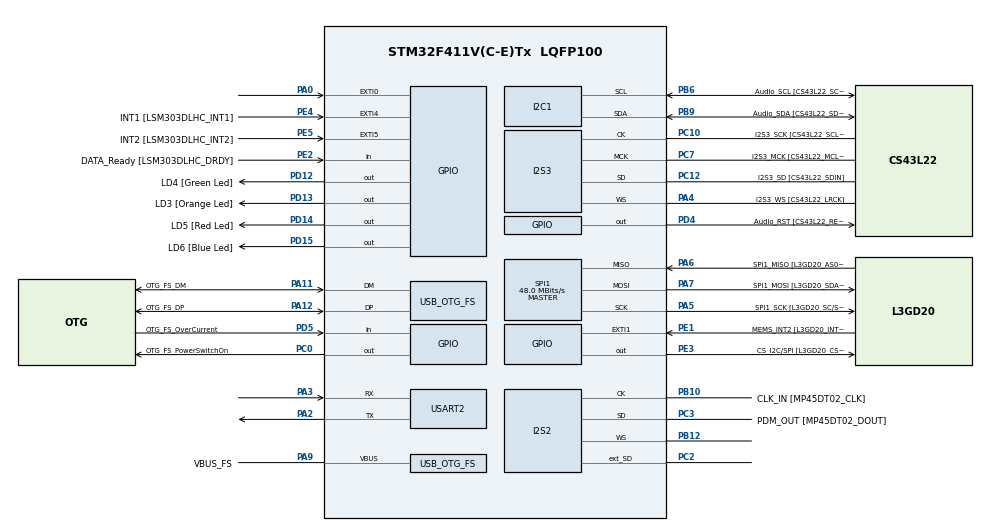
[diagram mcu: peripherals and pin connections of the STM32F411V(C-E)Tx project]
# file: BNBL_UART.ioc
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I2S2.AudioFreq=I2S_AUDIOFREQ_96K
I2S2.ErrorAudioFreq=0.15 %
I2S2.FullDuplexMode=I2S_FULLDUPLEXMODE_ENABLE
I2S2.Instance=SPI$Index
I2S2.RealAudioFreq=96.153 KHz
I2S2.VirtualMode=I2S_MODE_MASTER
I2S3.AudioFreq=I2S_AUDIOFREQ_96K
I2S3.ErrorAudioFreq=-6.99 %
I2S3.FullDuplexMode=I2S_FULLDUPLEXMODE_DISABLE
I2S3.Instance=SPI$Index
I2S3.RealAudioFreq=89.285 KHz
I2S3.VirtualMode=I2S_MODE_MASTER
Mcu.Family=STM32F4
Mcu.Name=STM32F411V(C-E)Tx
Mcu.Package=LQFP100
NVIC.OTG_FS_IRQn=true\:0\:0\:false\:false\:true\:true\:true\:true
NVIC.PriorityGroup=NVIC_PRIORITYGROUP_0
NVIC.USART2_IRQn=true\:0\:0\:false\:false\:true\:true\:true\:true
PA0-WKUP.GPIO_ModeDefaultEXTI=GPIO_MODE_EVT_RISING
PA0-WKUP.Signal=GPXTI0
PA10.GPIO_Label=OTG_FS_ID
PA10.Signal=USB_OTG_FS_ID
PA11.GPIO_Label=OTG_FS_DM
PA11.Mode=Device_Only
PA11.Signal=USB_OTG_FS_DM
PA12.GPIO_Label=OTG_FS_DP
PA12.Mode=Device_Only
PA12.Signal=USB_OTG_FS_DP
PA13.GPIO_Label=SWDIO
PA13.Mode=Serial_Wire
PA13.Signal=SYS_JTMS-SWDIO
PA14.GPIO_Label=SWCLK
PA14.Mode=Serial_Wire
PA14.Signal=SYS_JTCK-SWCLK
PA2.Mode=Asynchronous
PA2.Signal=USART2_TX
PA3.Mode=Asynchronous
PA3.Signal=USART2_RX
PA4.GPIO_Label=I2S3_WS [CS43L22_LRCK]
PA4.GPIO_Mode=GPIO_MODE_AF_PP
PA4.GPIO_PuPd=GPIO_NOPULL
PA4.GPIO_Speed=GPIO_SPEED_FREQ_LOW
PA4.Mode=Half_Duplex_Master
PA4.Signal=I2S3_WS
PA5.GPIO_Label=SPI1_SCK [L3GD20_SC/SPC]
PA5.Mode=Full_Duplex_Master
PA5.Signal=SPI1_SCK
PA6.GPIO_Label=SPI1_MISO [L3GD20_AS0/SDO]
PA6.Mode=Full_Duplex_Master
PA6.Signal=SPI1_MISO
PA7.GPIO_Label=SPI1_MOSI [L3GD20_SDA/SDI/SDO]
PA7.Mode=Full_Duplex_Master
PA7.Signal=SPI1_MOSI
PA9.GPIO_Label=VBUS_FS
PA9.Mode=Activate_VBUS
PA9.Signal=USB_OTG_FS_VBUS
PB10.GPIO_Label=CLK_IN [MP45DT02_CLK]
PB10.Mode=Full_Duplex_Master
PB10.Signal=I2S2_CK
PB12.Mode=Full_Duplex_Master
PB12.Signal=I2S2_WS
PB3.GPIO_Label=SWO
PB3.Signal=SYS_JTDO-SWO
PB6.GPIO_Label=Audio_SCL [CS43L22_SCL]
PB6.GPIO_Mode=GPIO_MODE_AF_OD
PB6.GPIO_Pu=GPIO_PULLUP
PB6.GPIO_PuPd=GPIO_NOPULL
PB6.GPIO_Speed=GPIO_SPEED_FREQ_LOW
PB6.Mode=I2C
PB6.Signal=I2C1_SCL
PB9.GPIO_Label=Audio_SDA [CS43L22_SDA]
PB9.GPIO_Mode=GPIO_MODE_AF_OD
PB9.GPIO_Pu=GPIO_PULLUP
PB9.GPIO_PuPd=GPIO_NOPULL
PB9.GPIO_Speed=GPIO_SPEED_FREQ_LOW
PB9.Mode=I2C
PB9.Signal=I2C1_SDA
PC0.GPIO_Label=OTG_FS_PowerSwitchOn
PC0.PinState=GPIO_PIN_SET
PC0.Signal=GPIO_Output
PC10.GPIO_Label=I2S3_SCK [CS43L22_SCLK]
PC10.GPIO_Mode=GPIO_MODE_AF_PP
PC10.GPIO_PuPd=GPIO_NOPULL
PC10.GPIO_Speed=GPIO_SPEED_FREQ_LOW
PC10.Mode=Half_Duplex_Master
PC10.Signal=I2S3_CK
PC12.GPIO_Label=I2S3_SD [CS43L22_SDIN]
PC12.GPIO_Mode=GPIO_MODE_AF_PP
PC12.GPIO_PuPd=GPIO_NOPULL
PC12.GPIO_Speed=GPIO_SPEED_FREQ_LOW
PC12.Mode=Half_Duplex_Master
PC12.Signal=I2S3_SD
PC14-OSC32_IN.GPIO_Label=PC14-OSC32_IN
PC14-OSC32_IN.Mode=LSE-External-Oscillator
PC14-OSC32_IN.Signal=RCC_OSC32_IN
PC15-OSC32_OUT.GPIO_Label=PC15-OSC32_OUT
PC15-OSC32_OUT.Mode=LSE-External-Oscillator
PC15-OSC32_OUT.Signal=RCC_OSC32_OUT
PC2.Mode=Full_Duplex_Master
PC2.Signal=I2S2_ext_SD
PC3.GPIO_Label=PDM_OUT [MP45DT02_DOUT]
PC3.Mode=Full_Duplex_Master
PC3.Signal=I2S2_SD
PC7.GPIO_Label=I2S3_MCK [CS43L22_MCLK]
PC7.GPIO_Mode=GPIO_MODE_AF_PP
PC7.GPIO_PuPd=GPIO_NOPULL
PC7.GPIO_Speed=GPIO_SPEED_FREQ_LOW
PC7.Mode=Master_Clock_Activated
PC7.Signal=I2S3_MCK
PD12.GPIO_Label=LD4 [Green Led]
PD12.GPIO_PuPd=GPIO_NOPULL
PD12.GPIO_Speed=GPIO_SPEED_FREQ_LOW
PD12.Signal=GPIO_Output
PD13.GPIO_Label=LD3 [Orange Led]
PD13.GPIO_PuPd=GPIO_NOPULL
PD13.GPIO_Speed=GPIO_SPEED_FREQ_LOW
PD13.Signal=GPIO_Output
PD14.GPIO_Label=LD5 [Red Led]
PD14.GPIO_PuPd=GPIO_NOPULL
PD14.GPIO_Speed=GPIO_SPEED_FREQ_LOW
PD14.Signal=GPIO_Output
PD15.GPIO_Label=LD6 [Blue Led]
PD15.GPIO_PuPd=GPIO_NOPULL
PD15.GPIO_Speed=GPIO_SPEED_FREQ_LOW
PD15.Signal=GPIO_Output
PD4.GPIO_Label=Audio_RST [CS43L22_RESET]
PD4.Signal=GPIO_Output
PD5.GPIO_Label=OTG_FS_OverCurrent
PD5.Signal=GPIO_Input
PE1.GPIO_Label=MEMS_INT2 [L3GD20_INT2]
PE1.GPIO_ModeDefaultEXTI=GPIO_MODE_EVT_RISING
PE1.Signal=GPXTI1
PE2.GPIO_Label=DATA_Ready [LSM303DLHC_DRDY]
PE2.Signal=GPIO_Input
PE3.GPIO_Label=CS_I2C/SPI [L3GD20_CS_I2C/SPI]
PE3.Signal=GPIO_Output
PE4.GPIO_Label=INT1 [LSM303DLHC_INT1]
PE4.GPIO_ModeDefaultEXTI=GPIO_MODE_EVT_RISING
PE4.Signal=GPXTI4
PE5.GPIO_Label=INT2 [LSM303DLHC_INT2]
PE5.GPIO_ModeDefaultEXTI=GPIO_MODE_EVT_RISING
PE5.Signal=GPXTI5
PH0\ -\ OSC_IN.GPIO_Label=PH0-OSC_IN
PH0\ -\ OSC_IN.Mode=HSE-External-Clock-Source
PH0\ -\ OSC_IN.Signal=RCC_OSC_IN
PH1\ -\ OSC_OUT.GPIO_Label=PH1-OSC_OUT
PH1\ -\ OSC_OUT.Mode=HSE-External-Clock-Source
PH1\ -\ OSC_OUT.Signal=RCC_OSC_OUT
ProjectManager.HeapSize=0x200
ProjectManager.StackSize=0x400
ProjectManager.TargetToolchain=STM32CubeIDE
RCC.48MHZClocksFreq_Value=48000000
RCC.AHBFreq_Value=96000000
RCC.APB1CLKDivider=RCC_HCLK_DIV4
RCC.APB1Freq_Value=24000000
RCC.APB1TimFreq_Value=48000000
RCC.APB2Freq_Value=96000000
RCC.APB2TimFreq_Value=96000000
RCC.CortexFreq_Value=96000000
RCC.HCLKFreq_Value=96000000
RCC.HSE_VALUE=8000000
RCC.HSI_VALUE=16000000
RCC.PLLI2SM=5
RCC.PLLI2SN=200
RCC.PLLM=4
RCC.PLLP=RCC_PLLP_DIV4
RCC.PLLQ=8
RCC.SYSCLKFreq_VALUE=96000000
RCC.SYSCLKSource=RCC_SYSCLKSOURCE_PLLCLK
RCC.VCOOutputFreq_Value=384000000
SPI1.BaudRatePrescaler=SPI_BAUDRATEPRESCALER_2
SPI1.CalculateBaudRate=48.0 MBits/s
SPI1.Direction=SPI_DIRECTION_2LINES
SPI1.Mode=SPI_MODE_MASTER
SPI1.VirtualType=VM_MASTER
USART2.VirtualMode=VM_ASYNC
USB_DEVICE.CLASS_NAME_FS=CDC
USB_DEVICE.VirtualMode=Cdc
USB_DEVICE.VirtualModeFS=Cdc_FS
USB_OTG_FS.VirtualMode=Device_Only
VP_USB_DEVICE_VS_USB_DEVICE_CDC_FS.Mode=CDC_FS
board=STM32F411E-DISCO

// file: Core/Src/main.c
/* USER CODE BEGIN Header */
/**
  ******************************************************************************
  * @file           : main.c
  * @brief          : Main program body
  ******************************************************************************
  * @attention
  *
  * Copyright (c) 2026 STMicroelectronics.
  * All rights reserved.
  *
  * This software is licensed under terms that can be found in the LICENSE file
  * in the root directory of this software component.
  * If no LICENSE file comes with this software, it is provided AS-IS.
  *
  ******************************************************************************
  */
/* USER CODE END Header */
#include "main.h"
#include "usb_device.h"
#include "usbd_cdc_if.h"

/* USER CODE BEGIN Includes */
#include <string.h>
#include <ctype.h>

/* USER CODE END Includes */

I2C_HandleTypeDef hi2c1;

I2S_HandleTypeDef hi2s2;
I2S_HandleTypeDef hi2s3;

SPI_HandleTypeDef hspi1;

UART_HandleTypeDef huart2;

/* USER CODE BEGIN PV */
#define RX_BUF_LEN 128
volatile uint8_t rxByte;
static char rxBuf[RX_BUF_LEN];
static volatile uint16_t rxIdx = 0;
volatile uint8_t fatigue_state = 0; // 0,1,2
#define USB_TX_BUF_LEN 512
static uint8_t usbTxBuf[USB_TX_BUF_LEN];
static volatile uint16_t usbTxHead = 0;
static volatile uint16_t usbTxTail = 0;

/* USER CODE END PV */

void SystemClock_Config(void);
void PeriphCommonClock_Config(void);
static void MX_GPIO_Init(void);
static void MX_I2C1_Init(void);
static void MX_I2S2_Init(void);
static void MX_I2S3_Init(void);
static void MX_SPI1_Init(void);
static void MX_USART2_UART_Init(void);

/* USER CODE BEGIN 0 */
static void usb_tx_push(uint8_t b)
{
  uint16_t next = (uint16_t)((usbTxHead + 1) % USB_TX_BUF_LEN);
  if (next == usbTxTail) {
    return;
  }
  usbTxBuf[usbTxHead] = b;
  usbTxHead = next;
}

static void usb_tx_flush(void)
{
  if (usbTxTail == usbTxHead) return;

  uint8_t chunk[64];
  uint16_t n = 0;

  while (usbTxTail != usbTxHead && n < sizeof(chunk)) {
    chunk[n++] = usbTxBuf[usbTxTail];
    usbTxTail = (uint16_t)((usbTxTail + 1) % USB_TX_BUF_LEN);
  }

  if (CDC_Transmit_FS(chunk, n) != USBD_OK) {
  }
}
static void parse_message_and_update_state(const char *msg)
{
  const char *p = strstr(msg, "\"status_code\"");
  if (!p) p = strstr(msg, "status_code");
  if (!p) return;

  p = strchr(p, ':');
  if (!p) return;
  p++;

  while (*p && isspace((unsigned char)*p)) p++;

  if (*p != '\"' && *p != '\'') return;
  char quote = *p;
  p++;

  char b0 = p[0];
  char b1 = p[1];
  if (!((b0=='0' || b0=='1') && (b1=='0' || b1=='1'))) return;

  if (b0=='0' && b1=='0') fatigue_state = 0;        // buden
  else if (b0=='0' && b1=='1') fatigue_state = 1;   // utrujen
  else if (b0=='1' && b1=='0') fatigue_state = 2;   // zaspan

static void usb_tx_push_str(const char *s)
{
  while (*s) usb_tx_push((uint8_t)*s++);
}

/* USER CODE END 0 */

int main(void)
{

  /* MCU Configuration--------------------------------------------------------*/

  /* Reset of all peripherals, Initializes the Flash interface and the Systick. */
   HAL_Init();

  /* Configure the system clock */
  SystemClock_Config();

  /* Configure the peripherals common clocks */
  PeriphCommonClock_Config();

  /* Initialize all configured peripherals */
  MX_GPIO_Init();
  MX_I2C1_Init();
  MX_I2S2_Init();
  MX_I2S3_Init();
  MX_SPI1_Init();
  MX_USB_DEVICE_Init();
  MX_USART2_UART_Init();
  HAL_UART_Receive_IT(&huart2, (uint8_t*)&rxByte, 1);

  /* Infinite loop */
  while (1)
  {

      //USER CODE BEGIN 3
	  usb_tx_flush();
	    HAL_Delay(500);

      switch(fatigue_state) {
          case 0:
              HAL_GPIO_WritePin(GPIOD, LD4_Pin, GPIO_PIN_SET);   // zeleni
              HAL_GPIO_WritePin(GPIOD, LD3_Pin, GPIO_PIN_RESET);
              HAL_GPIO_WritePin(GPIOD, LD5_Pin, GPIO_PIN_RESET);
              break;
          case 1:
              HAL_GPIO_WritePin(GPIOD, LD4_Pin, GPIO_PIN_RESET);
              HAL_GPIO_WritePin(GPIOD, LD3_Pin, GPIO_PIN_SET);   // narandžasti
              HAL_GPIO_WritePin(GPIOD, LD5_Pin, GPIO_PIN_RESET);
              break;
          case 2:
              HAL_GPIO_WritePin(GPIOD, LD3_Pin, GPIO_PIN_RESET);
              HAL_GPIO_WritePin(GPIOD, LD4_Pin, GPIO_PIN_RESET);
              HAL_GPIO_WritePin(GPIOD, LD5_Pin, GPIO_PIN_SET);   // crveni
              break;
      }

      HAL_Delay(50);
  }
  /* USER CODE END 3 */
}

void SystemClock_Config(void)
{
  RCC_OscInitTypeDef RCC_OscInitStruct = {0};
  RCC_ClkInitTypeDef RCC_ClkInitStruct = {0};

  /** Configure the main internal regulator output voltage
  */
  __HAL_RCC_PWR_CLK_ENABLE();
  __HAL_PWR_VOLTAGESCALING_CONFIG(PWR_REGULATOR_VOLTAGE_SCALE1);

  /** Initializes the RCC Oscillators according to the specified parameters
  * in the RCC_OscInitTypeDef structure.
  */
  RCC_OscInitStruct.OscillatorType = RCC_OSCILLATORTYPE_HSI;
  RCC_OscInitStruct.HSIState = RCC_HSI_ON;
  RCC_OscInitStruct.HSICalibrationValue = RCC_HSICALIBRATION_DEFAULT;
  RCC_OscInitStruct.PLL.PLLState = RCC_PLL_ON;
  RCC_OscInitStruct.PLL.PLLSource = RCC_PLLSOURCE_HSI;
  RCC_OscInitStruct.PLL.PLLM = 16;
  RCC_OscInitStruct.PLL.PLLN = 192;
  RCC_OscInitStruct.PLL.PLLP = RCC_PLLP_DIV4;
  RCC_OscInitStruct.PLL.PLLQ = 4;
  if (HAL_RCC_OscConfig(&RCC_OscInitStruct) != HAL_OK)
  {
    Error_Handler();
  }

  /** Initializes the CPU, AHB and APB buses clocks
  */
  RCC_ClkInitStruct.ClockType = RCC_CLOCKTYPE_HCLK|RCC_CLOCKTYPE_SYSCLK
                              |RCC_CLOCKTYPE_PCLK1|RCC_CLOCKTYPE_PCLK2;
  RCC_ClkInitStruct.SYSCLKSource = RCC_SYSCLKSOURCE_PLLCLK;
  RCC_ClkInitStruct.AHBCLKDivider = RCC_SYSCLK_DIV1;
  RCC_ClkInitStruct.APB1CLKDivider = RCC_HCLK_DIV4;
  RCC_ClkInitStruct.APB2CLKDivider = RCC_HCLK_DIV1;

  if (HAL_RCC_ClockConfig(&RCC_ClkInitStruct, FLASH_LATENCY_3) != HAL_OK)
  {
    Error_Handler();
  }
}

void PeriphCommonClock_Config(void)
{
  RCC_PeriphCLKInitTypeDef PeriphClkInitStruct = {0};

  /** Initializes the peripherals clock
  */
  PeriphClkInitStruct.PeriphClockSelection = RCC_PERIPHCLK_I2S;
  PeriphClkInitStruct.PLLI2S.PLLI2SN = 200;
  PeriphClkInitStruct.PLLI2S.PLLI2SM = 5;
  PeriphClkInitStruct.PLLI2S.PLLI2SR = 2;
  if (HAL_RCCEx_PeriphCLKConfig(&PeriphClkInitStruct) != HAL_OK)
  {
    Error_Handler();
  }
}

static void MX_I2C1_Init(void)
{

  hi2c1.Instance = I2C1;
  hi2c1.Init.ClockSpeed = 100000;
  hi2c1.Init.DutyCycle = I2C_DUTYCYCLE_2;
  hi2c1.Init.OwnAddress1 = 0;
  hi2c1.Init.AddressingMode = I2C_ADDRESSINGMODE_7BIT;
  hi2c1.Init.DualAddressMode = I2C_DUALADDRESS_DISABLE;
  hi2c1.Init.OwnAddress2 = 0;
  hi2c1.Init.GeneralCallMode = I2C_GENERALCALL_DISABLE;
  hi2c1.Init.NoStretchMode = I2C_NOSTRETCH_DISABLE;
  if (HAL_I2C_Init(&hi2c1) != HAL_OK)
  {
    Error_Handler();
  }

}

static void MX_I2S2_Init(void)
{

  hi2s2.Instance = SPI2;
  hi2s2.Init.Mode = I2S_MODE_MASTER_TX;
  hi2s2.Init.Standard = I2S_STANDARD_PHILIPS;
  hi2s2.Init.DataFormat = I2S_DATAFORMAT_16B;
  hi2s2.Init.MCLKOutput = I2S_MCLKOUTPUT_DISABLE;
  hi2s2.Init.AudioFreq = I2S_AUDIOFREQ_96K;
  hi2s2.Init.CPOL = I2S_CPOL_LOW;
  hi2s2.Init.ClockSource = I2S_CLOCK_PLL;
  hi2s2.Init.FullDuplexMode = I2S_FULLDUPLEXMODE_ENABLE;
  if (HAL_I2S_Init(&hi2s2) != HAL_OK)
  {
    Error_Handler();
  }

}

static void MX_I2S3_Init(void)
{

  hi2s3.Instance = SPI3;
  hi2s3.Init.Mode = I2S_MODE_MASTER_TX;
  hi2s3.Init.Standard = I2S_STANDARD_PHILIPS;
  hi2s3.Init.DataFormat = I2S_DATAFORMAT_16B;
  hi2s3.Init.MCLKOutput = I2S_MCLKOUTPUT_ENABLE;
  hi2s3.Init.AudioFreq = I2S_AUDIOFREQ_96K;
  hi2s3.Init.CPOL = I2S_CPOL_LOW;
  hi2s3.Init.ClockSource = I2S_CLOCK_PLL;
  hi2s3.Init.FullDuplexMode = I2S_FULLDUPLEXMODE_DISABLE;
  if (HAL_I2S_Init(&hi2s3) != HAL_OK)
  {
    Error_Handler();
  }

}

static void MX_SPI1_Init(void)
{

  /* SPI1 parameter configuration*/
  hspi1.Instance = SPI1;
  hspi1.Init.Mode = SPI_MODE_MASTER;
  hspi1.Init.Direction = SPI_DIRECTION_2LINES;
  hspi1.Init.DataSize = SPI_DATASIZE_8BIT;
  hspi1.Init.CLKPolarity = SPI_POLARITY_LOW;
  hspi1.Init.CLKPhase = SPI_PHASE_1EDGE;
  hspi1.Init.NSS = SPI_NSS_SOFT;
  hspi1.Init.BaudRatePrescaler = SPI_BAUDRATEPRESCALER_2;
  hspi1.Init.FirstBit = SPI_FIRSTBIT_MSB;
  hspi1.Init.TIMode = SPI_TIMODE_DISABLE;
  hspi1.Init.CRCCalculation = SPI_CRCCALCULATION_DISABLE;
  hspi1.Init.CRCPolynomial = 10;
  if (HAL_SPI_Init(&hspi1) != HAL_OK)
  {
    Error_Handler();
  }

}

static void MX_USART2_UART_Init(void)
{

  huart2.Instance = USART2;
  huart2.Init.BaudRate = 115200;
  huart2.Init.WordLength = UART_WORDLENGTH_8B;
  huart2.Init.StopBits = UART_STOPBITS_1;
  huart2.Init.Parity = UART_PARITY_NONE;
  huart2.Init.Mode = UART_MODE_TX_RX;
  huart2.Init.HwFlowCtl = UART_HWCONTROL_NONE;
  huart2.Init.OverSampling = UART_OVERSAMPLING_16;
  if (HAL_UART_Init(&huart2) != HAL_OK)
  {
    Error_Handler();
  }

}

static void MX_GPIO_Init(void)
{
  GPIO_InitTypeDef GPIO_InitStruct = {0};

  /* GPIO Ports Clock Enable */
  __HAL_RCC_GPIOE_CLK_ENABLE();
  __HAL_RCC_GPIOC_CLK_ENABLE();
  __HAL_RCC_GPIOH_CLK_ENABLE();
  __HAL_RCC_GPIOA_CLK_ENABLE();
  __HAL_RCC_GPIOB_CLK_ENABLE();
  __HAL_RCC_GPIOD_CLK_ENABLE();

  /*Configure GPIO pin Output Level */
  HAL_GPIO_WritePin(CS_I2C_SPI_GPIO_Port, CS_I2C_SPI_Pin, GPIO_PIN_RESET);

  /*Configure GPIO pin Output Level */
  HAL_GPIO_WritePin(OTG_FS_PowerSwitchOn_GPIO_Port, OTG_FS_PowerSwitchOn_Pin, GPIO_PIN_SET);

  /*Configure GPIO pin Output Level */
  HAL_GPIO_WritePin(GPIOD, LD4_Pin|LD3_Pin|LD5_Pin|LD6_Pin
                          |Audio_RST_Pin, GPIO_PIN_RESET);

  /*Configure GPIO pin : DATA_Ready_Pin */
  GPIO_InitStruct.Pin = DATA_Ready_Pin;
  GPIO_InitStruct.Mode = GPIO_MODE_INPUT;
  GPIO_InitStruct.Pull = GPIO_NOPULL;
  HAL_GPIO_Init(DATA_Ready_GPIO_Port, &GPIO_InitStruct);

  /*Configure GPIO pin : CS_I2C_SPI_Pin */
  GPIO_InitStruct.Pin = CS_I2C_SPI_Pin;
  GPIO_InitStruct.Mode = GPIO_MODE_OUTPUT_PP;
  GPIO_InitStruct.Pull = GPIO_NOPULL;
  GPIO_InitStruct.Speed = GPIO_SPEED_FREQ_LOW;
  HAL_GPIO_Init(CS_I2C_SPI_GPIO_Port, &GPIO_InitStruct);

  /*Configure GPIO pins : INT1_Pin INT2_Pin MEMS_INT2_Pin */
  GPIO_InitStruct.Pin = INT1_Pin|INT2_Pin|MEMS_INT2_Pin;
  GPIO_InitStruct.Mode = GPIO_MODE_EVT_RISING;
  GPIO_InitStruct.Pull = GPIO_NOPULL;
  HAL_GPIO_Init(GPIOE, &GPIO_InitStruct);

  /*Configure GPIO pin : OTG_FS_PowerSwitchOn_Pin */
  GPIO_InitStruct.Pin = OTG_FS_PowerSwitchOn_Pin;
  GPIO_InitStruct.Mode = GPIO_MODE_OUTPUT_PP;
  GPIO_InitStruct.Pull = GPIO_NOPULL;
  GPIO_InitStruct.Speed = GPIO_SPEED_FREQ_LOW;
  HAL_GPIO_Init(OTG_FS_PowerSwitchOn_GPIO_Port, &GPIO_InitStruct);

  /*Configure GPIO pin : PA0 */
  GPIO_InitStruct.Pin = GPIO_PIN_0;
  GPIO_InitStruct.Mode = GPIO_MODE_EVT_RISING;
  GPIO_InitStruct.Pull = GPIO_NOPULL;
  HAL_GPIO_Init(GPIOA, &GPIO_InitStruct);

  /*Configure GPIO pins : LD4_Pin LD3_Pin LD5_Pin LD6_Pin
                           Audio_RST_Pin */
  GPIO_InitStruct.Pin = LD4_Pin|LD3_Pin|LD5_Pin|LD6_Pin
                          |Audio_RST_Pin;
  GPIO_InitStruct.Mode = GPIO_MODE_OUTPUT_PP;
  GPIO_InitStruct.Pull = GPIO_NOPULL;
  GPIO_InitStruct.Speed = GPIO_SPEED_FREQ_LOW;
  HAL_GPIO_Init(GPIOD, &GPIO_InitStruct);

  /*Configure GPIO pin : OTG_FS_OverCurrent_Pin */
  GPIO_InitStruct.Pin = OTG_FS_OverCurrent_Pin;
  GPIO_InitStruct.Mode = GPIO_MODE_INPUT;
  GPIO_InitStruct.Pull = GPIO_NOPULL;
  HAL_GPIO_Init(OTG_FS_OverCurrent_GPIO_Port, &GPIO_InitStruct);

}

/* USER CODE BEGIN 4 */
void HAL_UART_RxCpltCallback(UART_HandleTypeDef *huart)
{
  if (huart->Instance == USART2)
  {
	HAL_GPIO_TogglePin(GPIOD, LD6_Pin);
    char c = (char)rxByte;
    usb_tx_push((uint8_t)c);

    if (rxIdx < RX_BUF_LEN - 1) {
      rxBuf[rxIdx++] = c;
      rxBuf[rxIdx] = '\0';
    } else {
      rxIdx = 0;
      rxBuf[0] = '\0';
    }

    if (c == '\n' || c == '}')
    {
      rxBuf[rxIdx] = '\0';
      parse_message_and_update_state(rxBuf);

      rxIdx = 0;
      rxBuf[0] = '\0';
    }

    HAL_UART_Receive_IT(&huart2, (uint8_t*)&rxByte, 1);
  }
}

/* USER CODE END 4 */

void Error_Handler(void)
{
  __disable_irq();
  while (1)
  {
  }
}
